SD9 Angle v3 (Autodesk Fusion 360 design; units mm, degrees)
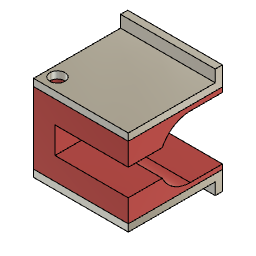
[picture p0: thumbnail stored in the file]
named bodies: "Frame", "Alu1", "Alu2"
